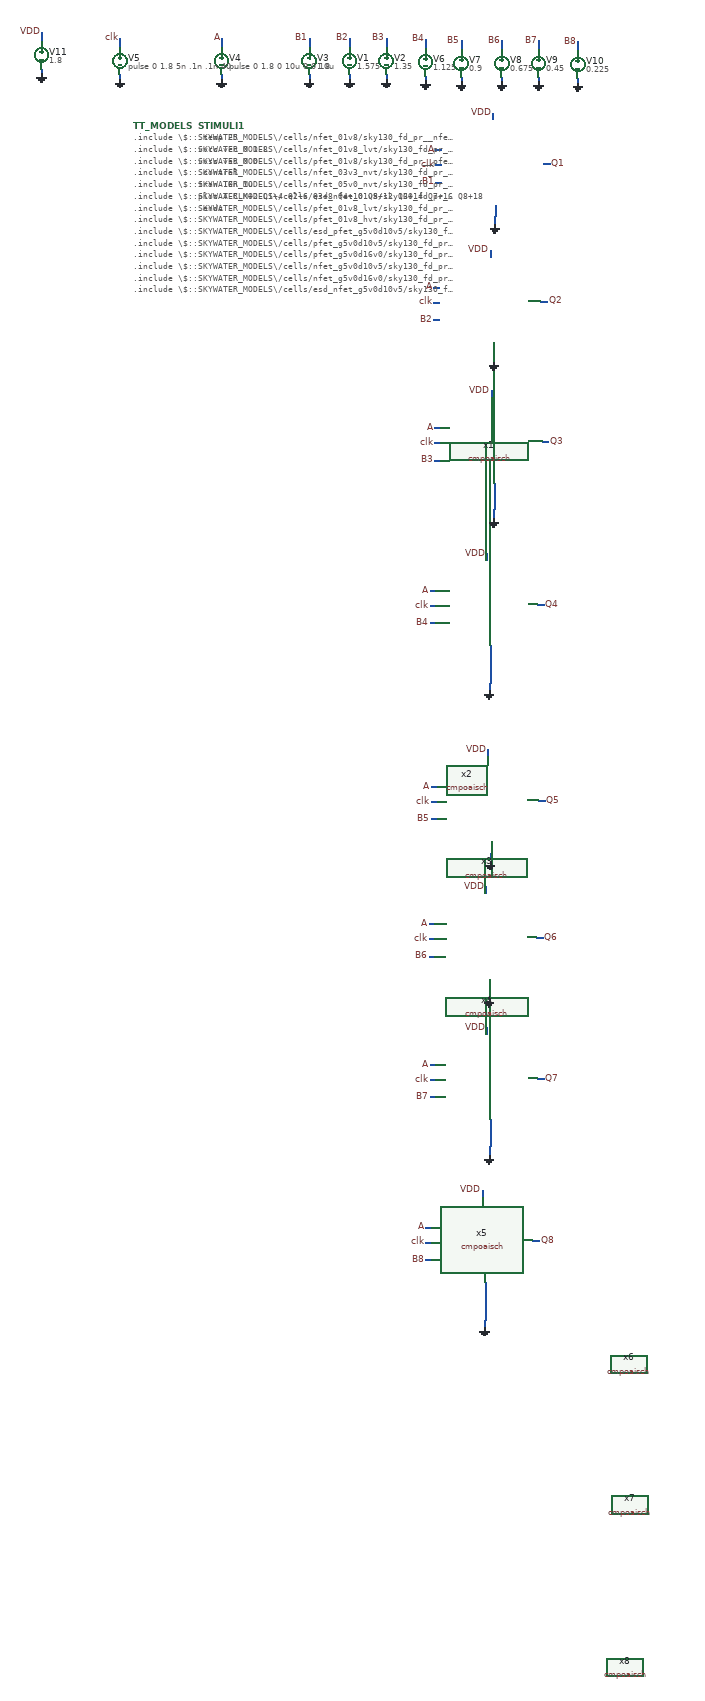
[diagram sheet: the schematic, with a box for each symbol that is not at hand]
v {xschem version=2.9.9 file_version=1.2 }
G {}
K {}
V {}
S {}
E {}
N -132.5 -1525 -132.5 -1520 { lab=GND}
N -132.5 -1542.5 -132.5 -1525 { lab=GND}
N -262.5 -1665 -250 -1665 { lab=A}
N -262.5 -1595 -250 -1595 { lab=B1}
N -132.5 -1545 -132.5 -1542.5 { lab=GND}
N -30 -1635 -15 -1635 { lab=Q1}
N -537.5 -1827.5 -537.5 -1817.5 { lab=GND}
N -727.5 -1827.5 -727.5 -1817.5 { lab=GND}
N -947.5 -1827.5 -947.5 -1817.5 { lab=GND}
N -947.5 -1907.5 -947.5 -1887.5 { lab=clk}
N -727.5 -1907.5 -727.5 -1887.5 { lab=A}
N -537.5 -1907.5 -537.5 -1887.5 { lab=B1}
N -450 -1827.5 -450 -1817.5 { lab=GND}
N -450 -1907.5 -450 -1887.5 { lab=B2}
N -370 -1827.5 -370 -1817.5 { lab=GND}
N -370 -1907.5 -370 -1887.5 { lab=B3}
N -285 -1825 -285 -1815 { lab=GND}
N -285 -1905 -285 -1885 { lab=B4}
N -207.5 -1822.5 -207.5 -1812.5 { lab=GND}
N -207.5 -1902.5 -207.5 -1882.5 { lab=B5}
N -120 -1822.5 -120 -1812.5 { lab=GND}
N -120 -1902.5 -120 -1882.5 { lab=B6}
N -40 -1822.5 -40 -1812.5 { lab=GND}
N -40 -1902.5 -40 -1882.5 { lab=B7}
N 45 -1820 45 -1810 { lab=GND}
N 45 -1900 45 -1880 { lab=B8}
N -1117.5 -1840 -1117.5 -1830 { lab=GND}
N -1117.5 -1920 -1117.5 -1900 { lab=VDD}
N -140 -1745 -140 -1730 { lab=VDD}
N -137.5 -1227.5 -137.5 -1222.5 { lab=GND}
N -137.5 -1245 -137.5 -1227.5 { lab=GND}
N -267.5 -1367.5 -255 -1367.5 { lab=A}
N -267.5 -1297.5 -255 -1297.5 { lab=B2}
N -137.5 -1247.5 -137.5 -1245 { lab=GND}
N -35 -1337.5 -20 -1337.5 { lab=Q2}
N -145 -1447.5 -145 -1432.5 { lab=VDD}
N -135 -922.5 -135 -917.5 { lab=GND}
N -135 -940 -135 -922.5 { lab=GND}
N -265 -1062.5 -252.5 -1062.5 { lab=A}
N -265 -992.5 -252.5 -992.5 { lab=B3}
N -135 -942.5 -135 -940 { lab=GND}
N -32.5 -1032.5 -17.5 -1032.5 { lab=Q3}
N -142.5 -1142.5 -142.5 -1127.5 { lab=VDD}
N -145 -570 -145 -565 { lab=GND}
N -145 -587.5 -145 -570 { lab=GND}
N -275 -710 -262.5 -710 { lab=A}
N -275 -640 -262.5 -640 { lab=B4}
N -145 -590 -145 -587.5 { lab=GND}
N -42.5 -680 -27.5 -680 { lab=Q4}
N -152.5 -790 -152.5 -775 { lab=VDD}
N -262.5 -1632.5 -250 -1632.5 { lab=clk}
N -267.5 -1335 -255 -1335 { lab=clk}
N -265 -1030 -252.5 -1030 { lab=clk}
N -275 -677.5 -262.5 -677.5 { lab=clk}
N -135 -1520 -135 -1502.5 { lab=GND}
N -135 -1520 -132.5 -1520 { lab=GND}
N -137.5 -1222.5 -137.5 -1202.5 { lab=GND}
N -135 -917.5 -135 -885 { lab=GND}
N -137.5 -885 -135 -885 { lab=GND}
N -137.5 -885 -137.5 -865 { lab=GND}
N -145 -565 -145 -507.5 { lab=GND}
N -147.5 -507.5 -145 -507.5 { lab=GND}
N -147.5 -507.5 -147.5 -492.5 { lab=GND}
N -142.5 -145 -142.5 -140 { lab=GND}
N -142.5 -162.5 -142.5 -145 { lab=GND}
N -272.5 -285 -260 -285 { lab=A}
N -272.5 -215 -260 -215 { lab=B5}
N -142.5 -165 -142.5 -162.5 { lab=GND}
N -40 -255 -25 -255 { lab=Q5}
N -150 -365 -150 -350 { lab=VDD}
N -147.5 152.5 -147.5 157.5 { lab=GND}
N -147.5 135 -147.5 152.5 { lab=GND}
N -277.5 12.5 -265 12.5 { lab=A}
N -277.5 82.5 -265 82.5 { lab=B6}
N -147.5 132.5 -147.5 135 { lab=GND}
N -45 42.5 -30 42.5 { lab=Q6}
N -155 -67.5 -155 -52.5 { lab=VDD}
N -145 457.5 -145 462.5 { lab=GND}
N -145 440 -145 457.5 { lab=GND}
N -275 317.5 -262.5 317.5 { lab=A}
N -275 387.5 -262.5 387.5 { lab=B7}
N -145 437.5 -145 440 { lab=GND}
N -42.5 347.5 -27.5 347.5 { lab=Q7}
N -152.5 237.5 -152.5 252.5 { lab=VDD}
N -155 810 -155 815 { lab=GND}
N -155 792.5 -155 810 { lab=GND}
N -285 670 -272.5 670 { lab=A}
N -285 740 -272.5 740 { lab=B8}
N -155 790 -155 792.5 { lab=GND}
N -52.5 700 -37.5 700 { lab=Q8}
N -162.5 590 -162.5 605 { lab=VDD}
N -272.5 -252.5 -260 -252.5 { lab=clk}
N -277.5 45 -265 45 { lab=clk}
N -275 350 -262.5 350 { lab=clk}
N -285 702.5 -272.5 702.5 { lab=clk}
N -145 -140 -145 -122.5 { lab=GND}
N -145 -140 -142.5 -140 { lab=GND}
N -147.5 157.5 -147.5 177.5 { lab=GND}
N -145 462.5 -145 495 { lab=GND}
N -147.5 495 -145 495 { lab=GND}
N -147.5 495 -147.5 515 { lab=GND}
N -155 815 -155 872.5 { lab=GND}
N -157.5 872.5 -155 872.5 { lab=GND}
N -157.5 872.5 -157.5 887.5 { lab=GND}
C {devices/lab_pin.sym} -262.5 -1665 0 0 {name=l1 sig_type=std_logic lab=A}
C {devices/lab_pin.sym} -262.5 -1595 0 0 {name=l2 sig_type=std_logic lab=B1}
C {devices/lab_pin.sym} -262.5 -1632.5 0 0 {name=l3 sig_type=std_logic lab=clk}
C {devices/lab_pin.sym} -15 -1635 2 0 {name=l4 sig_type=std_logic lab=Q1}
C {devices/vsource.sym} -537.5 -1857.5 0 0 {name=V3 value=1.8}
C {devices/vsource.sym} -727.5 -1857.5 0 0 {name=V4 value="pulse 0 1.8 0 10u 0 0 10u"}
C {devices/gnd.sym} -947.5 -1817.5 0 0 {name=l11 lab=GND}
C {devices/gnd.sym} -727.5 -1817.5 0 0 {name=l12 lab=GND}
C {devices/gnd.sym} -537.5 -1817.5 0 0 {name=l13 lab=GND}
C {devices/lab_pin.sym} -537.5 -1907.5 0 0 {name=l14 sig_type=std_logic lab=B1
}
C {devices/lab_pin.sym} -727.5 -1907.5 0 0 {name=l15 sig_type=std_logic lab=A
}
C {devices/lab_pin.sym} -947.5 -1907.5 0 0 {name=l16 sig_type=std_logic lab=clk}
C {devices/vsource.sym} -947.5 -1857.5 0 0 {name=V5 value="pulse 0 1.8 5n .1n .1n 40n 80n"}
C {devices/code.sym} -777.5 -1717.5 0 0 {name=STIMULI1 
only_toplevel=true
place=end
value="
.temp 25
vvcc vcc 0 1.8
vvss vss 0 0
.control
tran 10n 1u
plot A CLK+2 Q1+4 Q2+6 Q3+8 Q4+10 Q5+12 Q6+14 Q7+16 Q8+18
.endc
"}
C {devices/vsource.sym} -450 -1857.5 0 0 {name=V1 value=1.575}
C {devices/gnd.sym} -450 -1817.5 0 0 {name=l8 lab=GND}
C {devices/lab_pin.sym} -450 -1907.5 0 0 {name=l9 sig_type=std_logic lab=B2
}
C {devices/vsource.sym} -370 -1857.5 0 0 {name=V2 value=1.35}
C {devices/gnd.sym} -370 -1817.5 0 0 {name=l10 lab=GND}
C {devices/lab_pin.sym} -370 -1907.5 0 0 {name=l17 sig_type=std_logic lab=B3
}
C {devices/vsource.sym} -285 -1855 0 0 {name=V6 value=1.125}
C {devices/gnd.sym} -285 -1815 0 0 {name=l18 lab=GND}
C {devices/lab_pin.sym} -285 -1905 0 0 {name=l19 sig_type=std_logic lab=B4
}
C {devices/vsource.sym} -207.5 -1852.5 0 0 {name=V7 value=0.9}
C {devices/gnd.sym} -207.5 -1812.5 0 0 {name=l45 lab=GND}
C {devices/lab_pin.sym} -207.5 -1902.5 0 0 {name=l46 sig_type=std_logic lab=B5
}
C {devices/vsource.sym} -120 -1852.5 0 0 {name=V8 value=0.675}
C {devices/gnd.sym} -120 -1812.5 0 0 {name=l47 lab=GND}
C {devices/lab_pin.sym} -120 -1902.5 0 0 {name=l48 sig_type=std_logic lab=B6
}
C {devices/vsource.sym} -40 -1852.5 0 0 {name=V9 value=0.45}
C {devices/gnd.sym} -40 -1812.5 0 0 {name=l49 lab=GND}
C {devices/lab_pin.sym} -40 -1902.5 0 0 {name=l50 sig_type=std_logic lab=B7
}
C {devices/vsource.sym} 45 -1850 0 0 {name=V10 value=0.225}
C {devices/gnd.sym} 45 -1810 0 0 {name=l51 lab=GND}
C {devices/lab_pin.sym} 45 -1900 0 0 {name=l52 sig_type=std_logic lab=B8
}
C {devices/code.sym} -917.5 -1717.5 0 0 {name=TT_MODELS
only_toplevel=true
format="tcleval( @value )"
value="
.include \\\\$::SKYWATER_MODELS\\\\/cells/nfet_01v8/sky130_fd_pr__nfet_01v8__tt.corner.spice
.include \\\\$::SKYWATER_MODELS\\\\/cells/nfet_01v8_lvt/sky130_fd_pr__nfet_01v8_lvt__tt.corner.spice
.include \\\\$::SKYWATER_MODELS\\\\/cells/pfet_01v8/sky130_fd_pr__pfet_01v8__tt.corner.spice
.include \\\\$::SKYWATER_MODELS\\\\/cells/nfet_03v3_nvt/sky130_fd_pr__nfet_03v3_nvt__tt.corner.spice
.include \\\\$::SKYWATER_MODELS\\\\/cells/nfet_05v0_nvt/sky130_fd_pr__nfet_05v0_nvt__tt.corner.spice
.include \\\\$::SKYWATER_MODELS\\\\/cells/esd_nfet_01v8/sky130_fd_pr__esd_nfet_01v8__tt.corner.spice
.include \\\\$::SKYWATER_MODELS\\\\/cells/pfet_01v8_lvt/sky130_fd_pr__pfet_01v8_lvt__tt.corner.spice
.include \\\\$::SKYWATER_MODELS\\\\/cells/pfet_01v8_hvt/sky130_fd_pr__pfet_01v8_hvt__tt.corner.spice
.include \\\\$::SKYWATER_MODELS\\\\/cells/esd_pfet_g5v0d10v5/sky130_fd_pr__esd_pfet_g5v0d10v5__tt.corner.spice
.include \\\\$::SKYWATER_MODELS\\\\/cells/pfet_g5v0d10v5/sky130_fd_pr__pfet_g5v0d10v5__tt.corner.spice
.include \\\\$::SKYWATER_MODELS\\\\/cells/pfet_g5v0d16v0/sky130_fd_pr__pfet_g5v0d16v0__tt.corner.spice
.include \\\\$::SKYWATER_MODELS\\\\/cells/nfet_g5v0d10v5/sky130_fd_pr__nfet_g5v0d10v5__tt.corner.spice
.include \\\\$::SKYWATER_MODELS\\\\/cells/nfet_g5v0d16v0/sky130_fd_pr__nfet_g5v0d16v0__tt_discrete.corner.spice
.include \\\\$::SKYWATER_MODELS\\\\/cells/esd_nfet_g5v0d10v5/sky130_fd_pr__esd_nfet_g5v0d10v5__tt.corner.spice
.include \\\\$::SKYWATER_MODELS\\\\/models/corners/tt/nonfet.spice
* Mismatch parameters
.include \\\\$::SKYWATER_MODELS\\\\/cells/nfet_01v8/sky130_fd_pr__nfet_01v8__mismatch.corner.spice
.include \\\\$::SKYWATER_MODELS\\\\/cells/pfet_01v8/sky130_fd_pr__pfet_01v8__mismatch.corner.spice
.include \\\\$::SKYWATER_MODELS\\\\/cells/nfet_01v8_lvt/sky130_fd_pr__nfet_01v8_lvt__mismatch.corner.spice
.include \\\\$::SKYWATER_MODELS\\\\/cells/pfet_01v8_lvt/sky130_fd_pr__pfet_01v8_lvt__mismatch.corner.spice
.include \\\\$::SKYWATER_MODELS\\\\/cells/pfet_01v8_hvt/sky130_fd_pr__pfet_01v8_hvt__mismatch.corner.spice
.include \\\\$::SKYWATER_MODELS\\\\/cells/nfet_g5v0d10v5/sky130_fd_pr__nfet_g5v0d10v5__mismatch.corner.spice
.include \\\\$::SKYWATER_MODELS\\\\/cells/pfet_g5v0d10v5/sky130_fd_pr__pfet_g5v0d10v5__mismatch.corner.spice
.include \\\\$::SKYWATER_MODELS\\\\/cells/nfet_05v0_nvt/sky130_fd_pr__nfet_05v0_nvt__mismatch.corner.spice
.include \\\\$::SKYWATER_MODELS\\\\/cells/nfet_03v3_nvt/sky130_fd_pr__nfet_03v3_nvt__mismatch.corner.spice
* Resistor\\\\$::SKYWATER_MODELS\\\\/Capacitor
.include \\\\$::SKYWATER_MODELS\\\\/models/r+c/res_typical__cap_typical.spice
.include \\\\$::SKYWATER_MODELS\\\\/models/r+c/res_typical__cap_typical__lin.spice
* Special cells
.include \\\\$::SKYWATER_MODELS\\\\/models/corners/tt/specialized_cells.spice
* All models
.include \\\\$::SKYWATER_MODELS\\\\/models/all.spice
* Corner
.include \\\\$::SKYWATER_MODELS\\\\/models/corners/tt/rf.spice
.include ~/skywater-pdk/libraries/sky130_fd_sc_hd/latest/cells/nand3/sky130_fd_sc_hd__nand3_1.spice
.include ~/skywater-pdk/libraries/sky130_fd_sc_hd/latest/cells/nand2/sky130_fd_sc_hd__nand2_1.spice
.include ~/skywater-pdk/libraries/sky130_fd_sc_hd/latest/cells/nor3/sky130_fd_sc_hd__nor3_1.spice
.include ~/skywater-pdk/libraries/sky130_fd_sc_hd/latest/cells/dfrtp/sky130_fd_sc_hd__dfrtp_1.spice
.include ~/skywater-pdk/libraries/sky130_fd_sc_hd/latest/cells/nor2/sky130_fd_sc_hd__nor2_1.spice
.include ~/skywater-pdk/libraries/sky130_fd_sc_hd/latest/cells/dlrbn/sky130_fd_sc_hd__dlrbn_1.spice
.include ~/skywater-pdk/libraries/sky130_fd_sc_hd/latest/cells/a31o/sky130_fd_sc_hd__a31o_2.spice
.include ~/skywater-pdk/libraries/sky130_fd_sc_hd/latest/cells/inv/sky130_fd_sc_hd__inv_1.spice
.include ~/skywater-pdk/libraries/sky130_fd_sc_hd/latest/cells/a222oi/sky130_fd_sc_hd__a222oi_1.spice
.include ~/skywater-pdk/libraries/sky130_fd_sc_hd/latest/cells/or2/sky130_fd_sc_hd__or2_1.spice

"}
C {devices/vsource.sym} -1117.5 -1870 0 0 {name=V11 value=1.8}
C {devices/gnd.sym} -1117.5 -1830 0 0 {name=l53 lab=GND}
C {devices/lab_pin.sym} -1117.5 -1920 0 0 {name=l54 sig_type=std_logic lab=VDD
}
C {devices/lab_pin.sym} -140 -1745 0 0 {name=l57 sig_type=std_logic lab=VDD
}
C {devices/lab_pin.sym} -267.5 -1367.5 0 0 {name=l5 sig_type=std_logic lab=A}
C {devices/lab_pin.sym} -267.5 -1297.5 0 0 {name=l6 sig_type=std_logic lab=B2}
C {devices/lab_pin.sym} -267.5 -1335 0 0 {name=l7 sig_type=std_logic lab=clk}
C {devices/lab_pin.sym} -20 -1337.5 2 0 {name=l20 sig_type=std_logic lab=Q2}
C {devices/lab_pin.sym} -145 -1447.5 0 0 {name=l21 sig_type=std_logic lab=VDD
}
C {devices/lab_pin.sym} -265 -1062.5 0 0 {name=l23 sig_type=std_logic lab=A}
C {devices/lab_pin.sym} -265 -992.5 0 0 {name=l24 sig_type=std_logic lab=B3}
C {devices/lab_pin.sym} -265 -1030 0 0 {name=l25 sig_type=std_logic lab=clk}
C {devices/lab_pin.sym} -17.5 -1032.5 2 0 {name=l26 sig_type=std_logic lab=Q3}
C {devices/lab_pin.sym} -142.5 -1142.5 0 0 {name=l27 sig_type=std_logic lab=VDD
}
C {devices/lab_pin.sym} -275 -710 0 0 {name=l29 sig_type=std_logic lab=A}
C {devices/lab_pin.sym} -275 -640 0 0 {name=l30 sig_type=std_logic lab=B4}
C {devices/lab_pin.sym} -275 -677.5 0 0 {name=l31 sig_type=std_logic lab=clk}
C {devices/lab_pin.sym} -27.5 -680 2 0 {name=l32 sig_type=std_logic lab=Q4}
C {devices/lab_pin.sym} -152.5 -790 0 0 {name=l33 sig_type=std_logic lab=VDD
}
C {cmpoaisch.sym} 170 -710 0 0 {name=x1}
C {cmpoaisch.sym} 165 -412.5 0 0 {name=x2}
C {cmpoaisch.sym} 167.5 -107.5 0 0 {name=x3}
C {cmpoaisch.sym} 157.5 245 0 0 {name=x4}
C {devices/gnd.sym} -135 -1502.5 0 0 {name=l35 lab=GND}
C {devices/gnd.sym} -137.5 -1205 0 0 {name=l36 lab=GND}
C {devices/gnd.sym} -137.5 -865 0 0 {name=l37 lab=GND}
C {devices/gnd.sym} -147.5 -492.5 0 0 {name=l38 lab=GND}
C {devices/lab_pin.sym} -272.5 -285 0 0 {name=l22 sig_type=std_logic lab=A}
C {devices/lab_pin.sym} -272.5 -215 0 0 {name=l28 sig_type=std_logic lab=B5}
C {devices/lab_pin.sym} -272.5 -252.5 0 0 {name=l34 sig_type=std_logic lab=clk}
C {devices/lab_pin.sym} -25 -255 2 0 {name=l39 sig_type=std_logic lab=Q5}
C {devices/lab_pin.sym} -150 -365 0 0 {name=l40 sig_type=std_logic lab=VDD
}
C {devices/lab_pin.sym} -277.5 12.5 0 0 {name=l41 sig_type=std_logic lab=A}
C {devices/lab_pin.sym} -277.5 82.5 0 0 {name=l42 sig_type=std_logic lab=B6}
C {devices/lab_pin.sym} -277.5 45 0 0 {name=l43 sig_type=std_logic lab=clk}
C {devices/lab_pin.sym} -30 42.5 2 0 {name=l44 sig_type=std_logic lab=Q6}
C {devices/lab_pin.sym} -155 -67.5 0 0 {name=l55 sig_type=std_logic lab=VDD
}
C {devices/lab_pin.sym} -275 317.5 0 0 {name=l56 sig_type=std_logic lab=A}
C {devices/lab_pin.sym} -275 387.5 0 0 {name=l58 sig_type=std_logic lab=B7}
C {devices/lab_pin.sym} -275 350 0 0 {name=l59 sig_type=std_logic lab=clk}
C {devices/lab_pin.sym} -27.5 347.5 2 0 {name=l60 sig_type=std_logic lab=Q7}
C {devices/lab_pin.sym} -152.5 237.5 0 0 {name=l61 sig_type=std_logic lab=VDD
}
C {devices/lab_pin.sym} -285 670 0 0 {name=l62 sig_type=std_logic lab=A}
C {devices/lab_pin.sym} -285 740 0 0 {name=l63 sig_type=std_logic lab=B8}
C {devices/lab_pin.sym} -285 702.5 0 0 {name=l64 sig_type=std_logic lab=clk}
C {devices/lab_pin.sym} -37.5 700 2 0 {name=l65 sig_type=std_logic lab=Q8}
C {devices/lab_pin.sym} -162.5 590 0 0 {name=l66 sig_type=std_logic lab=VDD
}
C {cmpoaisch.sym} 160 670 0 0 {name=x5}
C {cmpoaisch.sym} 155 967.5 0 0 {name=x6}
C {cmpoaisch.sym} 157.5 1272.5 0 0 {name=x7}
C {cmpoaisch.sym} 147.5 1625 0 0 {name=x8}
C {devices/gnd.sym} -145 -122.5 0 0 {name=l67 lab=GND}
C {devices/gnd.sym} -147.5 175 0 0 {name=l68 lab=GND}
C {devices/gnd.sym} -147.5 515 0 0 {name=l69 lab=GND}
C {devices/gnd.sym} -157.5 887.5 0 0 {name=l70 lab=GND}
